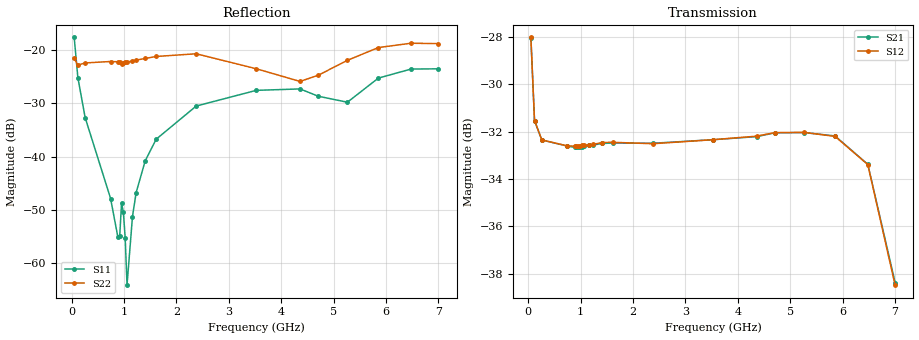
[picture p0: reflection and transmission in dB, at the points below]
! Integrated Device Technology
! Corporate Headquarters
! 6024 Silver Creek Valley Road
! San Jose, CA 95138  USA
! Phone:  1-408-284-8200
! Toll Free:  1-800-223-1366
! Webpage:  http://www.idt.com/
! Timing and RF Division
! 515 Groton Road, Suite 102
! Westford, MA 01886-6024
! Device:  F2258
! Description: Voltage Variable RF Attenuator
! Frequency:  50.0 -  6000.00 MHz
! Package:  3x3 mm Thin QFN Plastic Package: 16 pin
! Ports:  2 RF, 2 DC
!  Pin  1  = NC
!  Pin  2  = NC
!  Pin  3  = RF2  = Port 2
!  Pin  4  = GND
!  Pin  5  = Vdd
!  Pin  6  = NC
!  Pin  7  = VCTRL
!  Pin  8  = NC
!  Pin  9  = GND
!  Pin 10  = RF1  = Port 1
!  Pin 11  = NC
!  Pin 12  = NC
!  Pin 13  = NC
!  Pin 14  = NC
!  Pin 15  = NC
!  Pin 16  = NC
! Vcntrl:  1.760 Volts
! Vdd:  +3.300 Volts
! Current:  1.157 mA
! Data:  The device was measured on a the F2258 evaluation board which has
!  individual transmission lines to the RF pins.  Data was collected
!  using a calibrated network analyzer.  The evaluation board was
!  de-embedded using a TRL calibration technique.
!  The reference plane is the edge of the package pin.
! Misc:  SN 10
!  Action Tracker AT0285
! Date Measured:  2014-12-10
! Date:  2016-01-13  MJV
! Note:
!  Integrated Device Technology supplies this data as a sample of measured
!  data at the package pin for this product.  Your particular data for this
!  product may vary.
!  Data was taken at 25 degrees C.
!  Integrated Device Technology reserves the right to change this data at anytime.
!Freq_(GHz)  S11M_(dB)  S11P_(deg)  S21M_(dB)  S21P_(deg)  S12M_(dB)  S12P_(deg)  S22M_(dB)  S22P_(deg)
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# GHz S dB R 50
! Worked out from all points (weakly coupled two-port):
!   201 points, 50 MHz to 7 GHz, reference 50 ohm
!   highest |S21| = -28.03 dB at 50 MHz (marker M1); lowest = -38.4 dB at 7 GHz (marker M2)
!   lowest |S11| = -64.3 dB at 1.058 GHz (marker M3), VSWR 1.00, Z = 49.9 + j0.0352 ohm
!   |S11| at or under -10 dB: start of sweep to end of sweep
!   |S22| runs from -25.8 to -18.6 dB; largest |S21 - S12| = 0.00024
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0.05  -17.53 -110.4  -28.03 -57.5  -28.02 -57.5  -21.50 -77.1
0.1195  -25.10 -106.0  -31.53 -30.3  -31.53 -30.3  -22.76 -27.3
0.2585  -32.65 -110.0  -32.35 -16.1  -32.35 -16.1  -22.35 -12.0
0.745  -47.94 -135.0  -32.61 -9.9  -32.60 -9.9  -22.08 -7.5
0.884  -55.25 167.7  -32.66 -9.9  -32.61 -9.9  -22.13 -8.6
0.91875  -54.92 144.4  -32.65 -10.0  -32.60 -10.0  -22.13 -9.0
0.9535  -48.81 -155.7  -32.66 -10.0  -32.61 -10.0  -22.47 -7.6
0.98825  -50.52 -168.9  -32.64 -10.0  -32.61 -10.0  -22.43 -8.4
1.023  -55.36 178.8  -32.64 -10.1  -32.58 -10.1  -22.24 -8.8
1.05775  -64.26 144.9  -32.62 -10.1  -32.58 -10.1  -22.19 -8.7
1.162  -51.33 54.2  -32.58 -10.4  -32.56 -10.4  -21.97 -9.3
1.2315  -46.81 38.1  -32.57 -10.7  -32.54 -10.7  -21.82 -9.8
1.40525  -40.80 29.8  -32.50 -11.8  -32.46 -11.8  -21.50 -10.4
1.61375  -36.74 30.3  -32.48 -13.2  -32.45 -13.2  -21.13 -12.2
2.37825  -30.48 46.8  -32.49 -18.2  -32.51 -18.2  -20.62 -15.0
3.525  -27.52 90.9  -32.34 -26.6  -32.34 -26.6  -23.45 -21.5
4.359  -27.25 104.5  -32.21 -33.7  -32.19 -33.8  -25.84 -37.7
4.7065  -28.63 95.2  -32.05 -37.0  -32.04 -37.0  -24.67 -44.5
5.2625  -29.76 53.3  -32.04 -43.2  -32.03 -43.2  -21.86 -48.2
5.85325  -25.21 29.1  -32.18 -52.7  -32.20 -52.6  -19.45 -47.7
6.47875  -23.50 40.9  -33.38 -67.4  -33.39 -67.4  -18.63 -66.7
7  -23.46 84.1  -38.37 -67.6  -38.48 -67.3  -18.71 -123.4
